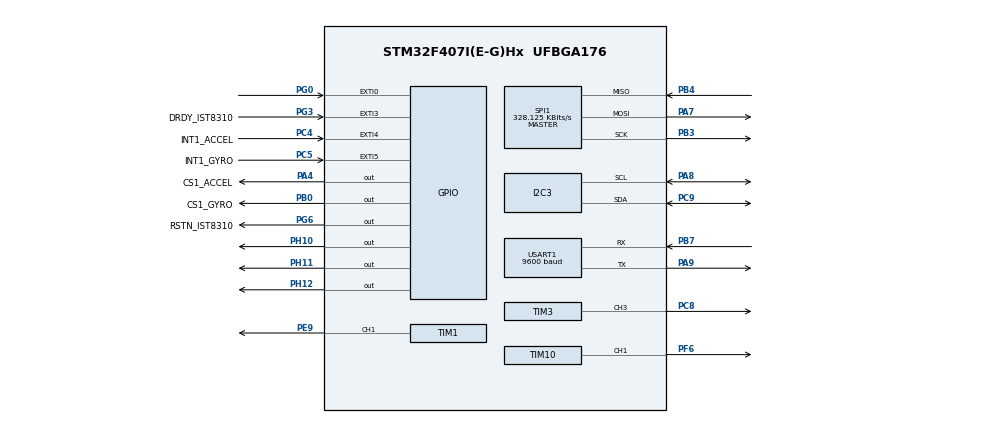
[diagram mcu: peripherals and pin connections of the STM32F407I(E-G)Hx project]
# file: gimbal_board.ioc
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Dma.Request0=SPI1_RX
Dma.Request1=SPI1_TX
Dma.SPI1_RX.0.Direction=DMA_PERIPH_TO_MEMORY
Dma.SPI1_RX.0.FIFOMode=DMA_FIFOMODE_DISABLE
Dma.SPI1_RX.0.Instance=DMA2_Stream2
Dma.SPI1_RX.0.MemDataAlignment=DMA_MDATAALIGN_BYTE
Dma.SPI1_RX.0.MemInc=DMA_MINC_ENABLE
Dma.SPI1_RX.0.Mode=DMA_NORMAL
Dma.SPI1_RX.0.PeriphDataAlignment=DMA_PDATAALIGN_BYTE
Dma.SPI1_RX.0.PeriphInc=DMA_PINC_DISABLE
Dma.SPI1_RX.0.Priority=DMA_PRIORITY_VERY_HIGH
Dma.SPI1_TX.1.Direction=DMA_MEMORY_TO_PERIPH
Dma.SPI1_TX.1.FIFOMode=DMA_FIFOMODE_DISABLE
Dma.SPI1_TX.1.Instance=DMA2_Stream3
Dma.SPI1_TX.1.MemDataAlignment=DMA_MDATAALIGN_BYTE
Dma.SPI1_TX.1.MemInc=DMA_MINC_ENABLE
Dma.SPI1_TX.1.Mode=DMA_NORMAL
Dma.SPI1_TX.1.PeriphDataAlignment=DMA_PDATAALIGN_BYTE
Dma.SPI1_TX.1.PeriphInc=DMA_PINC_DISABLE
Dma.SPI1_TX.1.Priority=DMA_PRIORITY_HIGH
FREERTOS.INCLUDE_pcTaskGetTaskName=1
FREERTOS.INCLUDE_uxTaskGetStackHighWaterMark2=1
FREERTOS.INCLUDE_vTaskCleanUpResources=1
FREERTOS.INCLUDE_xEventGroupSetBitFromISR=1
FREERTOS.INCLUDE_xSemaphoreGetMutexHolder=1
FREERTOS.INCLUDE_xTaskAbortDelay=1
FREERTOS.INCLUDE_xTaskGetHandle=1
FREERTOS.Tasks01=insTask,48,1024,INS_task,As weak,NULL,Dynamic,NULL,NULL
FREERTOS.configUSE_OS2_THREAD_ENUMERATE=0
FREERTOS.configUSE_TRACE_FACILITY=0
I2C3.I2C_Mode=I2C_Fast
Mcu.Family=STM32F4
Mcu.Name=STM32F407I(E-G)Hx
Mcu.Package=UFBGA176
NVIC.DMA2_Stream2_IRQn=true\:5\:0\:false\:false\:false\:true\:false\:true
NVIC.DMA2_Stream3_IRQn=true\:5\:0\:false\:false\:false\:true\:false\:true
NVIC.EXTI0_IRQn=true\:6\:0\:true\:false\:true\:true\:true\:true
NVIC.EXTI3_IRQn=true\:5\:0\:false\:false\:true\:true\:true\:true
NVIC.EXTI4_IRQn=true\:5\:0\:false\:false\:true\:true\:true\:true
NVIC.EXTI9_5_IRQn=true\:5\:0\:false\:false\:true\:true\:true\:true
NVIC.PriorityGroup=NVIC_PRIORITYGROUP_4
NVIC.USART1_IRQn=true\:5\:0\:false\:false\:true\:true\:true\:true
PA13.Mode=Serial_Wire
PA13.Signal=SYS_JTMS-SWDIO
PA14.Mode=Serial_Wire
PA14.Signal=SYS_JTCK-SWCLK
PA4.GPIO_Label=CS1_ACCEL
PA4.GPIO_PuPd=GPIO_PULLUP
PA4.GPIO_Speed=GPIO_SPEED_FREQ_HIGH
PA4.PinState=GPIO_PIN_SET
PA4.Signal=GPIO_Output
PA7.Mode=Full_Duplex_Master
PA7.Signal=SPI1_MOSI
PA8.GPIO_Pu=GPIO_PULLUP
PA8.Mode=I2C
PA8.Signal=I2C3_SCL
PA9.GPIO_PuPd=GPIO_PULLUP
PA9.Mode=Asynchronous
PA9.Signal=USART1_TX
PB0.GPIO_Label=CS1_GYRO
PB0.GPIO_PuPd=GPIO_PULLUP
PB0.GPIO_Speed=GPIO_SPEED_FREQ_HIGH
PB0.PinState=GPIO_PIN_SET
PB0.Signal=GPIO_Output
PB3.Mode=Full_Duplex_Master
PB3.Signal=SPI1_SCK
PB4.Mode=Full_Duplex_Master
PB4.Signal=SPI1_MISO
PB7.GPIO_PuPd=GPIO_PULLUP
PB7.Mode=Asynchronous
PB7.Signal=USART1_RX
PC4.GPIO_Label=INT1_ACCEL
PC4.GPIO_ModeDefaultEXTI=GPIO_MODE_IT_FALLING
PC4.GPIO_PuPd=GPIO_PULLUP
PC4.Signal=GPXTI4
PC5.GPIO_Label=INT1_GYRO
PC5.GPIO_ModeDefaultEXTI=GPIO_MODE_IT_FALLING
PC5.GPIO_PuPd=GPIO_PULLUP
PC5.Signal=GPXTI5
PC8.GPIO_PuPd=GPIO_PULLUP
PC8.GPIO_Speed=GPIO_SPEED_FREQ_HIGH
PC8.Signal=S_TIM3_CH3
PC9.GPIO_Pu=GPIO_PULLUP
PC9.Mode=I2C
PC9.Signal=I2C3_SDA
PE9.GPIO_PuPd=GPIO_PULLUP
PE9.GPIO_Speed=GPIO_SPEED_FREQ_HIGH
PE9.Signal=S_TIM1_CH1
PF6.GPIO_PuPd=GPIO_PULLUP
PF6.GPIO_Speed=GPIO_SPEED_FREQ_HIGH
PF6.Signal=S_TIM10_CH1
PG0.GPIO_ModeDefaultEXTI=GPIO_MODE_IT_FALLING
PG0.GPIO_PuPd=GPIO_PULLUP
PG0.Signal=GPXTI0
PG3.GPIO_Label=DRDY_IST8310
PG3.GPIO_ModeDefaultEXTI=GPIO_MODE_IT_FALLING
PG3.GPIO_PuPd=GPIO_PULLUP
PG3.Signal=GPXTI3
PG6.GPIO_Label=RSTN_IST8310
PG6.GPIO_PuPd=GPIO_PULLUP
PG6.GPIO_Speed=GPIO_SPEED_FREQ_MEDIUM
PG6.PinState=GPIO_PIN_SET
PG6.Signal=GPIO_Output
PH0-OSC_IN.Mode=HSE-External-Oscillator
PH0-OSC_IN.Signal=RCC_OSC_IN
PH1-OSC_OUT.Mode=HSE-External-Oscillator
PH1-OSC_OUT.Signal=RCC_OSC_OUT
PH10.GPIO_PuPd=GPIO_PULLUP
PH10.PinState=GPIO_PIN_SET
PH10.Signal=GPIO_Output
PH11.PinState=GPIO_PIN_SET
PH11.Signal=GPIO_Output
PH12.PinState=GPIO_PIN_SET
PH12.Signal=GPIO_Output
ProjectManager.HeapSize=0x200
ProjectManager.StackSize=0x400
ProjectManager.TargetToolchain=SW4STM32
RCC.48MHZClocksFreq_Value=84000000
RCC.AHBFreq_Value=168000000
RCC.APB1CLKDivider=RCC_HCLK_DIV4
RCC.APB1Freq_Value=42000000
RCC.APB1TimFreq_Value=84000000
RCC.APB2CLKDivider=RCC_HCLK_DIV2
RCC.APB2Freq_Value=84000000
RCC.APB2TimFreq_Value=168000000
RCC.CortexFreq_Value=168000000
RCC.HCLKFreq_Value=168000000
RCC.HSE_VALUE=12000000
RCC.HSI_VALUE=16000000
RCC.LSE_VALUE=32768
RCC.PLLM=6
RCC.PLLN=168
RCC.PLLSourceVirtual=RCC_PLLSOURCE_HSE
RCC.SYSCLKFreq_VALUE=168000000
RCC.SYSCLKSource=RCC_SYSCLKSOURCE_PLLCLK
RCC.VCOOutputFreq_Value=336000000
SH.S_TIM10_CH1.0=TIM10_CH1,PWM Generation1 CH1
SH.S_TIM1_CH1.0=TIM1_CH1,PWM Generation1 CH1
SH.S_TIM3_CH3.0=TIM3_CH3,PWM Generation3 CH3
SPI1.BaudRatePrescaler=SPI_BAUDRATEPRESCALER_256
SPI1.CLKPhase=SPI_PHASE_2EDGE
SPI1.CLKPolarity=SPI_POLARITY_HIGH
SPI1.CalculateBaudRate=328.125 KBits/s
SPI1.Direction=SPI_DIRECTION_2LINES
SPI1.Mode=SPI_MODE_MASTER
SPI1.VirtualType=VM_MASTER
STMicroelectronics.X-CUBE-ALGOBUILD.1.3.0.LibraryCcDSPOoLibraryJjDSPOoLibrary=true
TIM1.Channel-PWM\ Generation1\ CH1=TIM_CHANNEL_1
TIM1.Period=19999
TIM1.Prescaler=167
TIM1.Pulse-PWM\ Generation1\ CH1=2000
TIM10.Channel=TIM_CHANNEL_1
TIM10.Period=4999
TIM3.Channel-PWM\ Generation3\ CH3=TIM_CHANNEL_3
TIM3.Period=8399
USART1.BaudRate=9600
USART1.VirtualMode=VM_ASYNC
VP_FREERTOS_VS_CMSIS_V2.Mode=CMSIS_V2
VP_STMicroelectronics.X-CUBE-ALGOBUILD_VS_DSPOoLibraryJjLibrary_1.3.0_1.3.0.Mode=DSPOoLibraryJjLibrary
VP_TIM10_VS_ClockSourceINT.Mode=Enable_Timer
VP_TIM1_VS_ClockSourceINT.Mode=Internal
VP_TIM3_VS_ClockSourceINT.Mode=Internal
board=custom

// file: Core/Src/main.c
/* USER CODE BEGIN Header */
/**
  ******************************************************************************
  * @file           : main.c
  * @brief          : Main program body
  ******************************************************************************
  * @attention
  *
  * <h2><center>&copy; Copyright (c) 2022 STMicroelectronics.
  * All rights reserved.</center></h2>
  *
  * This software component is licensed by ST under Ultimate Liberty license
  * SLA0044, the "License"; You may not use this file except in compliance with
  * the License. You may obtain a copy of the License at:
  *                             www.st.com/SLA0044
  *
  ******************************************************************************
  */
/* USER CODE END Header */
#include "main.h"
#include "cmsis_os.h"
#include "dma.h"
#include "i2c.h"
#include "spi.h"
#include "tim.h"
#include "usart.h"
#include "gpio.h"

/* USER CODE BEGIN Includes */
#include "BMI088driver.h"
#include "ist8310driver.h"
#include "bsp_led.h"
#include "bsp_delay.h"
#include "bsp_usart.h"
#include "usart_task.h"
#include "INS_task.h"
/* USER CODE END Includes */

void SystemClock_Config(void);
void MX_FREERTOS_Init(void);

int main(void)
{

  /* MCU Configuration--------------------------------------------------------*/

  /* Reset of all peripherals, Initializes the Flash interface and the Systick. */
  HAL_Init();

  /* Configure the system clock */
  SystemClock_Config();

  /* Initialize all configured peripherals */
  MX_GPIO_Init();
  MX_DMA_Init();
  MX_I2C3_Init();
  MX_SPI1_Init();
  MX_TIM1_Init();
  MX_TIM3_Init();
  MX_TIM10_Init();
  MX_USART1_UART_Init();
  /* USER CODE BEGIN 2 */
    usart_init();
    delay_init();
    __HAL_TIM_SetCompare(&htim1, TIM_CHANNEL_1, PWM_OFF);
    led_off();
  /* USER CODE END 2 */

  /* Init scheduler */
  osKernelInitialize();  /* Call init function for freertos objects (in freertos.c) */
  MX_FREERTOS_Init();
  /* Start scheduler */
  osKernelStart();

  /* We should never get here as control is now taken by the scheduler */
  /* Infinite loop */
  while (1)
  {

  }
}

void SystemClock_Config(void)
{
  RCC_OscInitTypeDef RCC_OscInitStruct = {0};
  RCC_ClkInitTypeDef RCC_ClkInitStruct = {0};

  /** Configure the main internal regulator output voltage
  */
  __HAL_RCC_PWR_CLK_ENABLE();
  __HAL_PWR_VOLTAGESCALING_CONFIG(PWR_REGULATOR_VOLTAGE_SCALE1);

  /**
   * 先将时钟源选择为内部时钟
   * (怎么让CubeMX Generate的时候不删除这一段呢)
   */
  RCC_ClkInitStruct.ClockType = RCC_CLOCKTYPE_SYSCLK;
  RCC_ClkInitStruct.SYSCLKSource = RCC_SYSCLKSOURCE_HSI;
  if (HAL_RCC_ClockConfig(&RCC_ClkInitStruct, FLASH_LATENCY_5) != HAL_OK)
  {
    Error_Handler();
  }

  /** Initializes the RCC Oscillators according to the specified parameters
  * in the RCC_OscInitTypeDef structure.
  */
  RCC_OscInitStruct.OscillatorType = RCC_OSCILLATORTYPE_HSE;
  RCC_OscInitStruct.HSEState = RCC_HSE_ON;
  RCC_OscInitStruct.PLL.PLLState = RCC_PLL_ON;
  RCC_OscInitStruct.PLL.PLLSource = RCC_PLLSOURCE_HSE;
  RCC_OscInitStruct.PLL.PLLM = 6;
  RCC_OscInitStruct.PLL.PLLN = 168;
  RCC_OscInitStruct.PLL.PLLP = RCC_PLLP_DIV2;
  RCC_OscInitStruct.PLL.PLLQ = 4;
  if (HAL_RCC_OscConfig(&RCC_OscInitStruct) != HAL_OK)
  {
    Error_Handler();
  }
  /** Initializes the CPU, AHB and APB buses clocks
  */
  RCC_ClkInitStruct.ClockType = RCC_CLOCKTYPE_HCLK|RCC_CLOCKTYPE_SYSCLK
                              |RCC_CLOCKTYPE_PCLK1|RCC_CLOCKTYPE_PCLK2;
  RCC_ClkInitStruct.SYSCLKSource = RCC_SYSCLKSOURCE_PLLCLK;
  RCC_ClkInitStruct.AHBCLKDivider = RCC_SYSCLK_DIV1;
  RCC_ClkInitStruct.APB1CLKDivider = RCC_HCLK_DIV4;
  RCC_ClkInitStruct.APB2CLKDivider = RCC_HCLK_DIV2;

  if (HAL_RCC_ClockConfig(&RCC_ClkInitStruct, FLASH_LATENCY_5) != HAL_OK)
  {
    Error_Handler();
  }

  /**
   * 禁用内部高速时钟
   * (怎么让CubeMX Generate的时候不删除这一段呢)
   */
  RCC_OscInitStruct.OscillatorType = RCC_OSCILLATORTYPE_HSI;
  RCC_OscInitStruct.HSIState = RCC_HSI_OFF;
  RCC_OscInitStruct.PLL.PLLState = RCC_PLL_NONE;
  if(HAL_RCC_OscConfig(&RCC_OscInitStruct) != HAL_OK)
  {
    Error_Handler();
  }
}

void Error_Handler(void)
{
  __disable_irq();
  while (1)
  {
  }
}

/************************ (C) COPYRIGHT STMicroelectronics *****END OF FILE****/

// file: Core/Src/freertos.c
/* USER CODE BEGIN Header */
/**
  ******************************************************************************
  * File Name          : freertos.c
  * Description        : Code for freertos applications
  ******************************************************************************
  * @attention
  *
  * <h2><center>&copy; Copyright (c) 2022 STMicroelectronics.
  * All rights reserved.</center></h2>
  *
  * This software component is licensed by ST under Ultimate Liberty license
  * SLA0044, the "License"; You may not use this file except in compliance with
  * the License. You may obtain a copy of the License at:
  *                             www.st.com/SLA0044
  *
  ******************************************************************************
  */
/* USER CODE END Header */

#include "FreeRTOS.h"
#include "task.h"
#include "main.h"
#include "cmsis_os.h"

/* USER CODE BEGIN Includes */
#include "INS_task.h"
/* USER CODE END Includes */

/* Definitions for insTask */
osThreadId_t insTaskHandle;
const osThreadAttr_t insTask_attributes = {
  .name = "insTask",
  .stack_size = 1024 * 4,
  .priority = (osPriority_t) osPriorityRealtime,
};

void INS_task(void *argument);

void MX_FREERTOS_Init(void); /* (MISRA C 2004 rule 8.1) */

void MX_FREERTOS_Init(void) {

  /* Create the thread(s) */
  /* creation of insTask */
  insTaskHandle = osThreadNew(INS_task, NULL, &insTask_attributes);

}

__weak void INS_task(void *argument)
{
  for(;;)
  {
    osDelay(1);
  }
}

/************************ (C) COPYRIGHT STMicroelectronics *****END OF FILE****/
